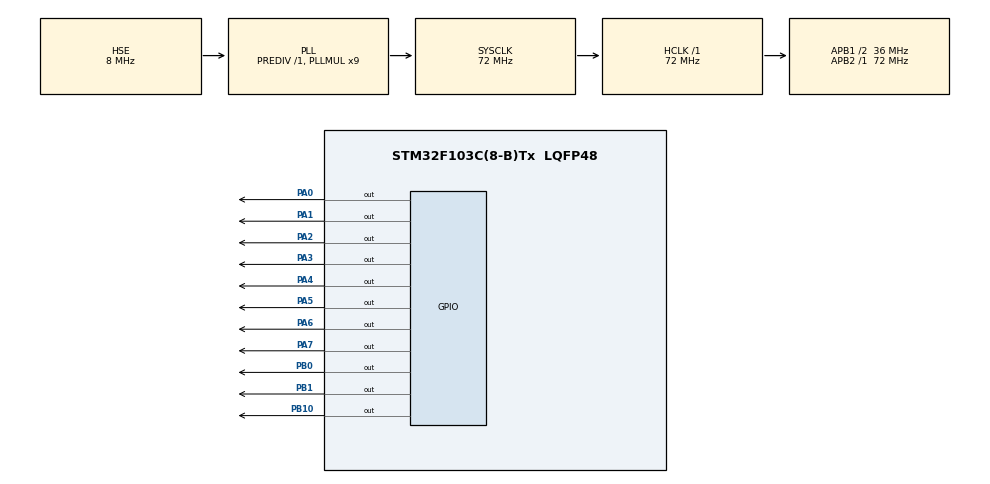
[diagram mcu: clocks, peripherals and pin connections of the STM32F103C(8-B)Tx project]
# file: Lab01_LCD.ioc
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Mcu.Family=STM32F1
Mcu.Name=STM32F103C(8-B)Tx
Mcu.Package=LQFP48
NVIC.PriorityGroup=NVIC_PRIORITYGROUP_4
PA0-WKUP.Signal=GPIO_Output
PA1.Signal=GPIO_Output
PA13.Mode=Serial_Wire
PA13.Signal=SYS_JTMS-SWDIO
PA14.Mode=Serial_Wire
PA14.Signal=SYS_JTCK-SWCLK
PA2.Signal=GPIO_Output
PA3.Signal=GPIO_Output
PA4.Signal=GPIO_Output
PA5.Signal=GPIO_Output
PA6.Signal=GPIO_Output
PA7.Signal=GPIO_Output
PB0.Signal=GPIO_Output
PB1.Signal=GPIO_Output
PB10.Signal=GPIO_Output
PD0-OSC_IN.Mode=HSE-External-Oscillator
PD0-OSC_IN.Signal=RCC_OSC_IN
PD1-OSC_OUT.Mode=HSE-External-Oscillator
PD1-OSC_OUT.Signal=RCC_OSC_OUT
ProjectManager.HeapSize=0x200
ProjectManager.StackSize=0x400
ProjectManager.TargetToolchain=CMake
RCC.AHBFreq_Value=72000000
RCC.APB1CLKDivider=RCC_HCLK_DIV2
RCC.APB1Freq_Value=36000000
RCC.APB1TimFreq_Value=72000000
RCC.APB2Freq_Value=72000000
RCC.APB2TimFreq_Value=72000000
RCC.HCLKFreq_Value=72000000
RCC.PLLMUL=RCC_PLL_MUL9
RCC.PLLSourceVirtual=RCC_PLLSOURCE_HSE
RCC.SYSCLKFreq_VALUE=72000000
RCC.SYSCLKSource=RCC_SYSCLKSOURCE_PLLCLK
RCC.USBFreq_Value=72000000
board=custom

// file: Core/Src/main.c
/* USER CODE BEGIN Header */
/**
  ******************************************************************************
  * @file           : main.c
  * @brief          : Main program body
  ******************************************************************************
  * @attention
  *
  * Copyright (c) 2026 STMicroelectronics.
  * All rights reserved.
  *
  * This software is licensed under terms that can be found in the LICENSE file
  * in the root directory of this software component.
  * If no LICENSE file comes with this software, it is provided AS-IS.
  *
  ******************************************************************************
  */
/* USER CODE END Header */
#include "main.h"

/* USER CODE BEGIN Includes */
#include "stdint.h"
#include "lcd1602.h"
#include "led7.h"
/* USER CODE END Includes */

void SystemClock_Config(void);
static void MX_GPIO_Init(void);

int main(void)
{

  /* USER CODE BEGIN 1 */
  mLCD.PORT_R = GPIOB;
  mLCD.PORT_DATA = GPIOA;
  mLCD.D0 = GPIO_PIN_0;
  mLCD.D1 = GPIO_PIN_1;
  mLCD.D2 = GPIO_PIN_2;
  mLCD.D3 = GPIO_PIN_3;
  mLCD.D4 = GPIO_PIN_4;
  mLCD.D5 = GPIO_PIN_5;
  mLCD.D6 = GPIO_PIN_6;
  mLCD.D7 = GPIO_PIN_7;
  mLCD.RS = GPIO_PIN_0;
  mLCD.RW = GPIO_PIN_1;
  mLCD.E = GPIO_PIN_10;

  /* USER CODE END 1 */

  /* MCU Configuration--------------------------------------------------------*/

  /* Reset of all peripherals, Initializes the Flash interface and the Systick. */
  HAL_Init();

  /* Configure the system clock */
  SystemClock_Config();

  /* Initialize all configured peripherals */
  MX_GPIO_Init();
  /* USER CODE BEGIN 2 */

  LCD_Init();
  LCD_Print_data("HELLO HELLO =))");
  HAL_Delay(100);
  LCD_Write_cmd(0x01); // Xóa chữ HELLO đi rồi mới vào while(1)
  HAL_GPIO_WritePin(GPIOB, GPIO_PIN_15, 1);
  Init_LED7(GPIOA, GPIO_PIN_8,
            GPIOA, GPIO_PIN_9,
            GPIOA, GPIO_PIN_10,
            GPIOA, GPIO_PIN_11,
            GPIOA, GPIO_PIN_12,
            GPIOB, GPIO_PIN_12,
            GPIOB, GPIO_PIN_13,
            GPIOB, GPIO_PIN_14,
            LED_ANODE
  );
  // uint8_t test = 'B';

  /* USER CODE END 2 */

  /* Infinite loop */
  while (1)
  {
    LCD_Print_data("Suprised in !!");
  Display_LED7(9);
  HAL_Delay(100);
  Display_LED7(8);
  HAL_Delay(100);
  Display_LED7(7);
  HAL_Delay(100);
  Display_LED7(6);
  HAL_Delay(100);
  Display_LED7(5);
  HAL_Delay(100);
  Display_LED7(4);
  HAL_Delay(100);
  Display_LED7(3);
  HAL_Delay(100);
  Display_LED7(2);
  HAL_Delay(100);
  Display_LED7(1);
  HAL_Delay(100);
  Display_LED7(0);
  LCD_Write_cmd(0x01);
  HAL_Delay(100);
  LCD_Print_data("Fuck You ");
  LCD_Write_cmd(0xC0);
  LCD_Print_data("Fargot!!");
  HAL_Delay(100);
  LCD_Write_cmd(0x01);
  HAL_Delay(100);

  }
}

void SystemClock_Config(void)
{
  RCC_OscInitTypeDef RCC_OscInitStruct = {0};
  RCC_ClkInitTypeDef RCC_ClkInitStruct = {0};

  /** Initializes the RCC Oscillators according to the specified parameters
  * in the RCC_OscInitTypeDef structure.
  */
  RCC_OscInitStruct.OscillatorType = RCC_OSCILLATORTYPE_HSE;
  RCC_OscInitStruct.HSEState = RCC_HSE_ON;
  RCC_OscInitStruct.HSEPredivValue = RCC_HSE_PREDIV_DIV1;
  RCC_OscInitStruct.HSIState = RCC_HSI_ON;
  RCC_OscInitStruct.PLL.PLLState = RCC_PLL_ON;
  RCC_OscInitStruct.PLL.PLLSource = RCC_PLLSOURCE_HSE;
  RCC_OscInitStruct.PLL.PLLMUL = RCC_PLL_MUL9;
  if (HAL_RCC_OscConfig(&RCC_OscInitStruct) != HAL_OK)
  {
    Error_Handler();
  }

  /** Initializes the CPU, AHB and APB buses clocks
  */
  RCC_ClkInitStruct.ClockType = RCC_CLOCKTYPE_HCLK|RCC_CLOCKTYPE_SYSCLK
                              |RCC_CLOCKTYPE_PCLK1|RCC_CLOCKTYPE_PCLK2;
  RCC_ClkInitStruct.SYSCLKSource = RCC_SYSCLKSOURCE_PLLCLK;
  RCC_ClkInitStruct.AHBCLKDivider = RCC_SYSCLK_DIV1;
  RCC_ClkInitStruct.APB1CLKDivider = RCC_HCLK_DIV2;
  RCC_ClkInitStruct.APB2CLKDivider = RCC_HCLK_DIV1;

  if (HAL_RCC_ClockConfig(&RCC_ClkInitStruct, FLASH_LATENCY_2) != HAL_OK)
  {
    Error_Handler();
  }
}

static void MX_GPIO_Init(void)
{
  GPIO_InitTypeDef GPIO_InitStruct = {0};

  /* GPIO Ports Clock Enable */
  __HAL_RCC_GPIOD_CLK_ENABLE();
  __HAL_RCC_GPIOA_CLK_ENABLE();
  __HAL_RCC_GPIOB_CLK_ENABLE();

  /*Configure GPIO pin Output Level */
  HAL_GPIO_WritePin(GPIOA, GPIO_PIN_0|GPIO_PIN_1|GPIO_PIN_2|GPIO_PIN_3
                          |GPIO_PIN_4|GPIO_PIN_5|GPIO_PIN_6|GPIO_PIN_7
                          |GPIO_PIN_8|GPIO_PIN_9|GPIO_PIN_10|GPIO_PIN_11
                          |GPIO_PIN_12, GPIO_PIN_RESET);

  /*Configure GPIO pin Output Level */
  HAL_GPIO_WritePin(GPIOB, GPIO_PIN_0|GPIO_PIN_1|GPIO_PIN_10|GPIO_PIN_12
                          |GPIO_PIN_13|GPIO_PIN_14|GPIO_PIN_15, GPIO_PIN_RESET);

  /*Configure GPIO pins : PA0 PA1 PA2 PA3
                           PA4 PA5 PA6 PA7
                           PA8 PA9 PA10 PA11
                           PA12 */
  GPIO_InitStruct.Pin = GPIO_PIN_0|GPIO_PIN_1|GPIO_PIN_2|GPIO_PIN_3
                          |GPIO_PIN_4|GPIO_PIN_5|GPIO_PIN_6|GPIO_PIN_7
                          |GPIO_PIN_8|GPIO_PIN_9|GPIO_PIN_10|GPIO_PIN_11
                          |GPIO_PIN_12;
  GPIO_InitStruct.Mode = GPIO_MODE_OUTPUT_PP;
  GPIO_InitStruct.Pull = GPIO_NOPULL;
  GPIO_InitStruct.Speed = GPIO_SPEED_FREQ_LOW;
  HAL_GPIO_Init(GPIOA, &GPIO_InitStruct);

  /*Configure GPIO pins : PB0 PB1 PB10 PB12
                           PB13 PB14 PB15 */
  GPIO_InitStruct.Pin = GPIO_PIN_0|GPIO_PIN_1|GPIO_PIN_10|GPIO_PIN_12
                          |GPIO_PIN_13|GPIO_PIN_14|GPIO_PIN_15;
  GPIO_InitStruct.Mode = GPIO_MODE_OUTPUT_PP;
  GPIO_InitStruct.Pull = GPIO_NOPULL;
  GPIO_InitStruct.Speed = GPIO_SPEED_FREQ_LOW;
  HAL_GPIO_Init(GPIOB, &GPIO_InitStruct);

}

void Error_Handler(void)
{
  __disable_irq();
  while (1)
  {
  }
}
